VERSION 5.7 ;
  NOWIREEXTENSIONATPIN ON ;
  DIVIDERCHAR "/" ;
  BUSBITCHARS "[]" ;
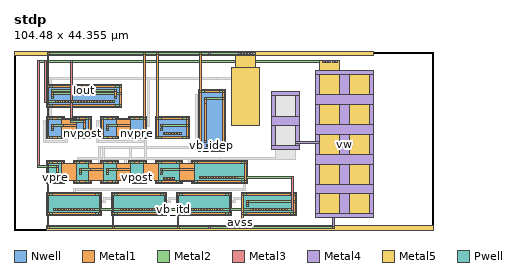
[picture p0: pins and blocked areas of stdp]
MACRO stdp
  CLASS BLOCK ;
  FOREIGN stdp ;
  ORIGIN 0.000 -0.310 ;
  SIZE 104.480 BY 44.355 ;
  PIN avdd
    USE POWER ;
    PORT
      LAYER Nwell ;
        RECT 8.000 30.865 26.860 36.465 ;
        RECT 8.000 22.965 12.490 28.565 ;
        RECT 14.790 22.965 19.280 28.565 ;
        RECT 21.580 22.965 26.070 28.565 ;
        RECT 28.370 22.965 32.860 28.565 ;
        RECT 35.160 22.965 43.620 28.565 ;
        RECT 45.920 19.920 52.580 35.210 ;
      LAYER Metal1 ;
        RECT 8.230 43.915 8.730 44.415 ;
        RECT 32.170 43.915 32.670 44.415 ;
        RECT 35.390 43.915 35.890 44.415 ;
        RECT 46.150 43.915 46.650 44.415 ;
        RECT 8.230 36.255 8.690 43.915 ;
        RECT 8.230 35.755 8.730 36.255 ;
        RECT 9.580 35.755 25.280 36.255 ;
        RECT 26.130 35.755 26.630 36.255 ;
        RECT 8.230 31.575 8.690 35.755 ;
        RECT 26.170 34.560 26.630 35.755 ;
        RECT 9.400 34.060 9.900 34.560 ;
        RECT 26.130 34.060 26.630 34.560 ;
        RECT 9.420 33.510 9.880 34.060 ;
        RECT 9.400 33.010 9.900 33.510 ;
        RECT 26.170 31.575 26.630 34.060 ;
        RECT 8.230 31.075 8.730 31.575 ;
        RECT 9.580 31.075 25.280 31.575 ;
        RECT 26.130 31.075 26.630 31.575 ;
        RECT 8.230 28.355 8.690 31.075 ;
        RECT 32.170 28.355 32.630 43.915 ;
        RECT 8.230 27.855 8.730 28.355 ;
        RECT 9.595 27.855 10.895 28.355 ;
        RECT 11.760 27.925 12.260 28.355 ;
        RECT 15.020 27.925 15.520 28.355 ;
        RECT 11.760 27.855 15.520 27.925 ;
        RECT 16.385 27.855 17.685 28.355 ;
        RECT 18.550 27.855 19.050 28.355 ;
        RECT 8.230 23.675 8.690 27.855 ;
        RECT 11.800 26.660 15.480 27.855 ;
        RECT 9.400 26.160 9.900 26.660 ;
        RECT 11.760 26.160 15.480 26.660 ;
        RECT 9.420 25.610 9.880 26.160 ;
        RECT 9.400 25.110 9.900 25.610 ;
        RECT 11.800 23.675 15.480 26.160 ;
        RECT 18.590 23.675 19.050 27.855 ;
        RECT 8.230 23.175 8.730 23.675 ;
        RECT 9.595 23.175 10.895 23.675 ;
        RECT 11.760 23.605 15.520 23.675 ;
        RECT 11.760 23.175 12.260 23.605 ;
        RECT 15.020 23.175 15.520 23.605 ;
        RECT 16.385 23.175 17.685 23.675 ;
        RECT 18.550 23.175 19.050 23.675 ;
        RECT 21.810 27.855 22.310 28.355 ;
        RECT 23.175 27.855 24.475 28.355 ;
        RECT 25.340 27.925 25.840 28.355 ;
        RECT 28.600 27.925 29.100 28.355 ;
        RECT 25.340 27.855 29.100 27.925 ;
        RECT 29.965 27.855 31.265 28.355 ;
        RECT 32.130 27.855 32.630 28.355 ;
        RECT 21.810 23.675 22.270 27.855 ;
        RECT 25.380 26.660 29.060 27.855 ;
        RECT 22.980 26.160 23.480 26.660 ;
        RECT 25.340 26.160 29.060 26.660 ;
        RECT 23.000 25.610 23.460 26.160 ;
        RECT 22.980 25.110 23.480 25.610 ;
        RECT 25.380 23.675 29.060 26.160 ;
        RECT 32.170 23.675 32.630 27.855 ;
        RECT 21.810 23.175 22.310 23.675 ;
        RECT 23.175 23.175 24.475 23.675 ;
        RECT 25.340 23.605 29.100 23.675 ;
        RECT 25.340 23.175 25.840 23.605 ;
        RECT 28.600 23.175 29.100 23.605 ;
        RECT 29.965 23.175 31.265 23.675 ;
        RECT 32.130 23.175 32.630 23.675 ;
        RECT 35.390 28.355 35.850 43.915 ;
        RECT 46.150 35.000 46.610 43.915 ;
        RECT 46.150 34.500 46.650 35.000 ;
        RECT 47.400 34.500 51.100 35.000 ;
        RECT 51.850 34.500 52.350 35.000 ;
        RECT 35.390 27.855 35.890 28.355 ;
        RECT 36.740 27.855 42.040 28.355 ;
        RECT 42.890 27.855 43.390 28.355 ;
        RECT 35.390 23.675 35.850 27.855 ;
        RECT 42.930 26.660 43.390 27.855 ;
        RECT 36.560 26.160 37.060 26.660 ;
        RECT 42.890 26.160 43.390 26.660 ;
        RECT 36.580 25.610 37.040 26.160 ;
        RECT 36.560 25.110 37.060 25.610 ;
        RECT 42.930 23.675 43.390 26.160 ;
        RECT 35.390 23.175 35.890 23.675 ;
        RECT 36.740 23.175 42.040 23.675 ;
        RECT 42.890 23.175 43.390 23.675 ;
        RECT 46.150 20.630 46.610 34.500 ;
        RECT 51.890 33.310 52.350 34.500 ;
        RECT 47.320 32.810 47.820 33.310 ;
        RECT 51.850 32.810 52.350 33.310 ;
        RECT 47.340 31.810 47.800 32.810 ;
        RECT 47.320 22.510 47.820 31.810 ;
        RECT 47.340 22.060 47.800 22.510 ;
        RECT 51.890 20.630 52.350 32.810 ;
        RECT 46.150 20.130 46.650 20.630 ;
        RECT 47.400 20.130 51.100 20.630 ;
        RECT 51.850 20.130 52.350 20.630 ;
      LAYER Metal2 ;
        RECT 8.230 43.915 60.080 44.415 ;
        RECT 8.230 35.755 26.630 36.255 ;
        RECT 9.400 34.060 26.630 34.560 ;
        RECT 46.150 34.500 52.350 35.000 ;
        RECT 9.400 33.010 9.900 33.510 ;
        RECT 47.320 32.810 52.350 33.310 ;
        RECT 8.230 31.075 26.630 31.575 ;
        RECT 8.230 27.855 12.260 28.355 ;
        RECT 15.020 27.855 19.050 28.355 ;
        RECT 21.810 27.855 25.840 28.355 ;
        RECT 28.600 27.855 32.630 28.355 ;
        RECT 35.390 27.855 43.390 28.355 ;
        RECT 9.400 26.160 12.260 26.660 ;
        RECT 22.980 26.160 25.840 26.660 ;
        RECT 36.560 26.160 43.390 26.660 ;
        RECT 9.400 25.110 9.900 25.610 ;
        RECT 22.980 25.110 23.480 25.610 ;
        RECT 36.560 25.110 37.060 25.610 ;
        RECT 8.230 23.175 12.260 23.675 ;
        RECT 15.020 23.175 19.050 23.675 ;
        RECT 21.810 23.175 25.840 23.675 ;
        RECT 28.600 23.175 32.630 23.675 ;
        RECT 35.390 23.175 43.390 23.675 ;
        RECT 47.320 22.060 47.820 32.260 ;
        RECT 46.150 20.130 52.350 20.630 ;
      LAYER Metal3 ;
        RECT 48.490 43.915 48.990 44.415 ;
        RECT 55.730 43.915 56.230 44.415 ;
        RECT 56.530 43.915 57.030 44.415 ;
        RECT 57.330 43.915 57.830 44.415 ;
        RECT 58.130 43.915 58.630 44.415 ;
        RECT 58.930 43.915 59.430 44.415 ;
      LAYER Metal4 ;
        RECT 48.490 43.915 48.990 44.415 ;
        RECT 55.730 43.915 56.230 44.415 ;
        RECT 56.530 43.915 57.030 44.415 ;
        RECT 57.330 43.915 57.830 44.415 ;
        RECT 58.130 43.915 58.630 44.415 ;
        RECT 58.930 43.915 59.430 44.415 ;
      LAYER Metal5 ;
        RECT 0.000 43.665 89.480 44.665 ;
        RECT 55.080 40.665 60.080 43.665 ;
        RECT 54.080 26.265 61.080 40.665 ;
    END
  END avdd
  PIN avss
    USE GROUND ;
    PORT
      LAYER Pwell ;
        RECT 8.000 11.910 12.490 17.510 ;
        RECT 14.790 11.910 19.280 17.510 ;
        RECT 21.580 11.910 26.070 17.510 ;
        RECT 28.370 11.910 32.860 17.510 ;
        RECT 35.160 11.855 41.820 17.565 ;
        RECT 44.120 11.910 57.980 17.510 ;
        RECT 8.000 4.010 21.860 9.610 ;
        RECT 24.160 4.010 38.020 9.610 ;
        RECT 40.320 4.010 54.180 9.610 ;
        RECT 56.480 4.010 70.340 9.610 ;
      LAYER Metal1 ;
        RECT 8.230 16.800 8.730 17.300 ;
        RECT 9.595 16.800 10.895 17.300 ;
        RECT 11.760 16.870 12.260 17.300 ;
        RECT 15.020 16.870 15.520 17.300 ;
        RECT 11.760 16.800 15.520 16.870 ;
        RECT 16.385 16.800 17.685 17.300 ;
        RECT 18.550 16.870 19.050 17.300 ;
        RECT 21.810 16.870 22.310 17.300 ;
        RECT 18.550 16.800 22.310 16.870 ;
        RECT 23.175 16.800 24.475 17.300 ;
        RECT 25.340 16.870 25.840 17.300 ;
        RECT 28.600 16.870 29.100 17.300 ;
        RECT 25.340 16.800 29.100 16.870 ;
        RECT 29.965 16.800 31.265 17.300 ;
        RECT 32.130 16.870 32.630 17.300 ;
        RECT 35.390 16.870 35.890 17.355 ;
        RECT 32.130 16.855 35.890 16.870 ;
        RECT 36.640 16.855 40.340 17.355 ;
        RECT 41.090 16.925 41.590 17.355 ;
        RECT 44.350 16.925 44.850 17.300 ;
        RECT 41.090 16.855 44.850 16.925 ;
        RECT 32.130 16.800 35.850 16.855 ;
        RECT 8.230 12.620 8.690 16.800 ;
        RECT 11.800 12.620 15.480 16.800 ;
        RECT 18.590 15.605 22.270 16.800 ;
        RECT 25.380 15.605 29.060 16.800 ;
        RECT 16.190 15.105 16.690 15.605 ;
        RECT 18.550 15.105 22.270 15.605 ;
        RECT 22.980 15.105 23.480 15.605 ;
        RECT 25.340 15.105 29.060 15.605 ;
        RECT 16.210 14.555 16.670 15.105 ;
        RECT 16.190 14.055 16.690 14.555 ;
        RECT 18.590 12.620 22.270 15.105 ;
        RECT 23.000 14.555 23.460 15.105 ;
        RECT 22.980 14.055 23.480 14.555 ;
        RECT 25.380 12.620 29.060 15.105 ;
        RECT 32.170 12.620 35.850 16.800 ;
        RECT 41.130 16.800 44.850 16.855 ;
        RECT 45.600 16.800 56.500 17.300 ;
        RECT 57.250 16.800 57.750 17.300 ;
        RECT 41.130 15.665 44.810 16.800 ;
        RECT 36.560 15.165 37.060 15.665 ;
        RECT 41.090 15.165 44.810 15.665 ;
        RECT 36.580 14.560 37.040 15.165 ;
        RECT 36.560 14.060 37.060 14.560 ;
        RECT 36.580 14.005 37.040 14.060 ;
        RECT 8.230 12.120 8.730 12.620 ;
        RECT 9.595 12.120 10.895 12.620 ;
        RECT 11.760 12.550 15.520 12.620 ;
        RECT 11.760 12.120 12.260 12.550 ;
        RECT 15.020 12.120 15.520 12.550 ;
        RECT 16.385 12.120 17.685 12.620 ;
        RECT 18.550 12.550 22.310 12.620 ;
        RECT 18.550 12.120 19.050 12.550 ;
        RECT 21.810 12.120 22.310 12.550 ;
        RECT 23.175 12.120 24.475 12.620 ;
        RECT 25.340 12.550 29.100 12.620 ;
        RECT 25.340 12.120 25.840 12.550 ;
        RECT 28.600 12.120 29.100 12.550 ;
        RECT 29.965 12.120 31.265 12.620 ;
        RECT 32.130 12.565 35.850 12.620 ;
        RECT 41.130 12.620 44.810 15.165 ;
        RECT 57.290 12.620 57.750 16.800 ;
        RECT 41.130 12.565 44.850 12.620 ;
        RECT 32.130 12.550 35.890 12.565 ;
        RECT 32.130 12.120 32.630 12.550 ;
        RECT 8.230 9.400 8.690 12.120 ;
        RECT 35.390 12.065 35.890 12.550 ;
        RECT 36.640 12.065 40.340 12.565 ;
        RECT 41.090 12.495 44.850 12.565 ;
        RECT 41.090 12.065 41.590 12.495 ;
        RECT 44.350 12.120 44.850 12.495 ;
        RECT 45.600 12.120 56.500 12.620 ;
        RECT 57.250 12.120 57.750 12.620 ;
        RECT 8.230 8.900 8.730 9.400 ;
        RECT 9.480 8.900 20.380 9.400 ;
        RECT 21.130 8.900 21.630 9.400 ;
        RECT 8.230 4.720 8.690 8.900 ;
        RECT 21.170 4.720 21.630 8.900 ;
        RECT 8.230 4.220 8.730 4.720 ;
        RECT 9.480 4.220 20.380 4.720 ;
        RECT 21.130 4.220 21.630 4.720 ;
        RECT 24.390 8.900 24.890 9.400 ;
        RECT 25.640 8.900 36.540 9.400 ;
        RECT 37.290 8.900 37.790 9.400 ;
        RECT 24.390 4.720 24.850 8.900 ;
        RECT 37.330 4.720 37.790 8.900 ;
        RECT 24.390 4.220 24.890 4.720 ;
        RECT 25.640 4.220 36.540 4.720 ;
        RECT 37.290 4.220 37.790 4.720 ;
        RECT 40.550 8.900 41.050 9.400 ;
        RECT 41.800 8.900 52.700 9.400 ;
        RECT 53.450 8.900 53.950 9.400 ;
        RECT 40.550 4.720 41.010 8.900 ;
        RECT 53.490 4.720 53.950 8.900 ;
        RECT 40.550 4.220 41.050 4.720 ;
        RECT 41.800 4.220 52.700 4.720 ;
        RECT 53.450 4.220 53.950 4.720 ;
        RECT 56.710 8.900 57.210 9.400 ;
        RECT 57.960 8.900 68.860 9.400 ;
        RECT 69.610 8.900 70.110 9.400 ;
        RECT 56.710 4.720 57.170 8.900 ;
        RECT 69.650 7.705 70.110 8.900 ;
        RECT 57.880 7.205 58.380 7.705 ;
        RECT 69.610 7.205 70.110 7.705 ;
        RECT 57.900 6.655 58.360 7.205 ;
        RECT 57.880 6.155 58.380 6.655 ;
        RECT 69.650 4.720 70.110 7.205 ;
        RECT 56.710 4.220 57.210 4.720 ;
        RECT 57.960 4.220 68.860 4.720 ;
        RECT 69.610 4.220 70.110 4.720 ;
        RECT 8.230 1.060 8.690 4.220 ;
        RECT 24.390 1.060 24.850 4.220 ;
        RECT 40.550 1.060 41.010 4.220 ;
        RECT 56.710 1.060 57.170 4.220 ;
        RECT 8.230 0.560 8.730 1.060 ;
        RECT 24.390 0.560 24.890 1.060 ;
        RECT 40.550 0.560 41.050 1.060 ;
        RECT 56.670 0.560 57.170 1.060 ;
      LAYER Metal2 ;
        RECT 8.230 16.800 12.260 17.300 ;
        RECT 15.020 16.800 19.050 17.300 ;
        RECT 21.810 16.800 25.840 17.300 ;
        RECT 28.600 16.800 32.630 17.300 ;
        RECT 35.390 16.855 41.590 17.355 ;
        RECT 44.350 16.800 57.750 17.300 ;
        RECT 16.190 15.105 19.050 15.605 ;
        RECT 22.980 15.105 25.840 15.605 ;
        RECT 36.560 15.165 41.590 15.665 ;
        RECT 16.190 14.055 16.690 14.555 ;
        RECT 22.980 14.055 23.480 14.555 ;
        RECT 36.560 14.005 37.060 14.615 ;
        RECT 8.230 12.120 12.260 12.620 ;
        RECT 15.020 12.120 19.050 12.620 ;
        RECT 21.810 12.120 25.840 12.620 ;
        RECT 28.600 12.120 32.630 12.620 ;
        RECT 35.390 12.065 41.590 12.565 ;
        RECT 44.350 12.120 57.750 12.620 ;
        RECT 8.230 8.900 21.630 9.400 ;
        RECT 24.390 8.900 37.790 9.400 ;
        RECT 40.550 8.900 53.950 9.400 ;
        RECT 56.710 8.900 70.110 9.400 ;
        RECT 57.880 7.205 70.110 7.705 ;
        RECT 57.880 6.155 58.380 6.655 ;
        RECT 8.230 4.220 21.630 4.720 ;
        RECT 24.390 4.220 37.790 4.720 ;
        RECT 40.550 4.220 53.950 4.720 ;
        RECT 56.710 4.220 70.110 4.720 ;
        RECT 8.230 0.560 79.630 1.060 ;
      LAYER Metal3 ;
        RECT 48.490 0.560 48.990 1.060 ;
        RECT 79.130 0.560 79.630 1.060 ;
      LAYER Metal4 ;
        RECT 75.080 38.910 89.480 39.910 ;
        RECT 64.080 33.665 71.080 34.665 ;
        RECT 64.080 28.665 65.080 33.665 ;
        RECT 70.080 28.665 71.080 33.665 ;
        RECT 64.080 26.265 71.080 28.665 ;
        RECT 64.080 21.265 65.080 26.265 ;
        RECT 70.080 22.415 71.080 26.265 ;
        RECT 75.080 33.910 76.080 38.910 ;
        RECT 81.080 33.910 83.480 38.910 ;
        RECT 88.480 33.910 89.480 38.910 ;
        RECT 75.080 31.510 89.480 33.910 ;
        RECT 75.080 26.510 76.080 31.510 ;
        RECT 81.080 26.510 83.480 31.510 ;
        RECT 88.480 26.510 89.480 31.510 ;
        RECT 75.080 24.110 89.480 26.510 ;
        RECT 75.080 22.415 76.080 24.110 ;
        RECT 70.080 21.915 76.080 22.415 ;
        RECT 70.080 21.265 71.080 21.915 ;
        RECT 64.080 20.265 71.080 21.265 ;
        RECT 75.080 19.110 76.080 21.915 ;
        RECT 81.080 19.110 83.480 24.110 ;
        RECT 88.480 19.110 89.480 24.110 ;
        RECT 75.080 16.710 89.480 19.110 ;
        RECT 75.080 11.710 76.080 16.710 ;
        RECT 81.080 11.710 83.480 16.710 ;
        RECT 88.480 11.710 89.480 16.710 ;
        RECT 75.080 9.310 89.480 11.710 ;
        RECT 75.080 4.310 76.080 9.310 ;
        RECT 81.080 4.310 83.480 9.310 ;
        RECT 88.480 4.310 89.480 9.310 ;
        RECT 75.080 3.310 89.480 4.310 ;
        RECT 48.490 0.560 48.990 1.060 ;
        RECT 79.130 0.560 79.630 3.310 ;
      LAYER Metal5 ;
        RECT 8.000 0.310 104.480 1.310 ;
    END
  END avss
  PIN nvpost
    ANTENNAGATEAREA 0.315000 ;
    PORT
      LAYER Metal1 ;
        RECT 16.785 24.070 17.285 24.570 ;
      LAYER Metal2 ;
        RECT 16.720 24.070 17.350 24.570 ;
      LAYER Metal3 ;
        RECT 16.850 24.070 17.350 24.570 ;
      LAYER Metal4 ;
        RECT 16.850 24.070 17.350 24.570 ;
    END
  END nvpost
  PIN nvpre
    ANTENNAGATEAREA 0.315000 ;
    PORT
      LAYER Metal1 ;
        RECT 30.365 24.070 30.865 24.570 ;
      LAYER Metal2 ;
        RECT 30.300 24.070 30.930 24.570 ;
      LAYER Metal3 ;
        RECT 30.430 24.070 30.930 24.570 ;
      LAYER Metal4 ;
        RECT 30.430 24.070 30.930 24.570 ;
    END
  END nvpre
  PIN vpost
    ANTENNAGATEAREA 0.315000 ;
    PORT
      LAYER Metal1 ;
        RECT 30.365 13.015 30.865 13.515 ;
      LAYER Metal2 ;
        RECT 30.300 13.015 30.930 13.515 ;
      LAYER Metal3 ;
        RECT 30.430 13.015 30.930 13.515 ;
      LAYER Metal4 ;
        RECT 30.430 13.015 30.930 13.515 ;
    END
  END vpost
  PIN vpre
    ANTENNAGATEAREA 0.315000 ;
    PORT
      LAYER Metal1 ;
        RECT 9.995 13.015 10.495 13.515 ;
      LAYER Metal2 ;
        RECT 9.930 13.015 10.560 13.515 ;
      LAYER Metal3 ;
        RECT 10.060 13.015 10.560 13.515 ;
      LAYER Metal4 ;
        RECT 10.060 13.015 10.560 13.515 ;
    END
  END vpre
  PIN vb_idep
    ANTENNAGATEAREA 28.559999 ;
    PORT
      LAYER Metal1 ;
        RECT 48.200 21.020 48.700 21.520 ;
        RECT 49.000 21.020 49.500 21.520 ;
        RECT 49.800 21.020 50.300 21.520 ;
      LAYER Metal2 ;
        RECT 47.850 21.020 50.650 21.520 ;
      LAYER Metal3 ;
        RECT 50.150 21.020 50.650 21.520 ;
      LAYER Metal4 ;
        RECT 50.150 21.020 50.650 21.520 ;
    END
  END vb_idep
  PIN vb_itd
    ANTENNAGATEAREA 25.000000 ;
    PORT
      LAYER Metal1 ;
        RECT 46.400 13.015 46.900 13.515 ;
        RECT 47.200 13.015 47.700 13.515 ;
        RECT 48.000 13.015 48.500 13.515 ;
        RECT 48.800 13.015 49.300 13.515 ;
        RECT 49.600 13.015 50.100 13.515 ;
        RECT 50.400 13.015 50.900 13.515 ;
        RECT 51.200 13.015 51.700 13.515 ;
        RECT 52.000 13.015 52.500 13.515 ;
        RECT 52.800 13.015 53.300 13.515 ;
        RECT 53.600 13.015 54.100 13.515 ;
        RECT 54.400 13.015 54.900 13.515 ;
        RECT 55.200 13.015 55.700 13.515 ;
        RECT 10.280 5.115 10.780 5.615 ;
        RECT 11.080 5.115 11.580 5.615 ;
        RECT 11.880 5.115 12.380 5.615 ;
        RECT 12.680 5.115 13.180 5.615 ;
        RECT 13.480 5.115 13.980 5.615 ;
        RECT 14.280 5.115 14.780 5.615 ;
        RECT 15.080 5.115 15.580 5.615 ;
        RECT 15.880 5.115 16.380 5.615 ;
        RECT 16.680 5.115 17.180 5.615 ;
        RECT 17.480 5.115 17.980 5.615 ;
        RECT 18.280 5.115 18.780 5.615 ;
        RECT 19.080 5.115 19.580 5.615 ;
        RECT 26.440 5.115 26.940 5.615 ;
        RECT 27.240 5.115 27.740 5.615 ;
        RECT 28.040 5.115 28.540 5.615 ;
        RECT 28.840 5.115 29.340 5.615 ;
        RECT 29.640 5.115 30.140 5.615 ;
        RECT 30.440 5.115 30.940 5.615 ;
        RECT 31.240 5.115 31.740 5.615 ;
        RECT 32.040 5.115 32.540 5.615 ;
        RECT 32.840 5.115 33.340 5.615 ;
        RECT 33.640 5.115 34.140 5.615 ;
        RECT 34.440 5.115 34.940 5.615 ;
        RECT 35.240 5.115 35.740 5.615 ;
        RECT 42.600 5.115 43.100 5.615 ;
        RECT 43.400 5.115 43.900 5.615 ;
        RECT 44.200 5.115 44.700 5.615 ;
        RECT 45.000 5.115 45.500 5.615 ;
        RECT 45.800 5.115 46.300 5.615 ;
        RECT 46.600 5.115 47.100 5.615 ;
        RECT 47.400 5.115 47.900 5.615 ;
        RECT 48.200 5.115 48.700 5.615 ;
        RECT 49.000 5.115 49.500 5.615 ;
        RECT 49.800 5.115 50.300 5.615 ;
        RECT 50.600 5.115 51.100 5.615 ;
        RECT 51.400 5.115 51.900 5.615 ;
        RECT 58.760 5.115 59.260 5.615 ;
        RECT 59.560 5.115 60.060 5.615 ;
        RECT 60.360 5.115 60.860 5.615 ;
        RECT 61.160 5.115 61.660 5.615 ;
        RECT 61.960 5.115 62.460 5.615 ;
        RECT 62.760 5.115 63.260 5.615 ;
        RECT 63.560 5.115 64.060 5.615 ;
        RECT 64.360 5.115 64.860 5.615 ;
        RECT 65.160 5.115 65.660 5.615 ;
        RECT 65.960 5.115 66.460 5.615 ;
        RECT 66.760 5.115 67.260 5.615 ;
        RECT 67.560 5.115 68.060 5.615 ;
      LAYER Metal2 ;
        RECT 46.050 13.015 69.410 13.515 ;
        RECT 9.930 5.115 69.410 5.615 ;
      LAYER Metal3 ;
        RECT 19.430 5.115 19.930 5.615 ;
        RECT 68.910 5.115 69.410 13.515 ;
      LAYER Metal4 ;
        RECT 19.430 5.115 19.930 5.615 ;
    END
  END vb_itd
  PIN vb_itp
    ANTENNAGATEAREA 2.300000 ;
    PORT
      LAYER Metal1 ;
        RECT 37.540 24.070 38.040 24.570 ;
        RECT 38.340 24.070 38.840 24.570 ;
        RECT 39.140 24.070 39.640 24.570 ;
        RECT 39.940 24.070 40.440 24.570 ;
        RECT 40.740 24.070 41.240 24.570 ;
      LAYER Metal2 ;
        RECT 37.090 24.070 41.690 24.570 ;
      LAYER Metal3 ;
        RECT 41.190 24.070 41.690 24.570 ;
      LAYER Metal4 ;
        RECT 41.190 24.070 41.690 24.570 ;
    END
  END vb_itp
  PIN vb_pot
    ANTENNAGATEAREA 1.708000 ;
    PORT
      LAYER Metal1 ;
        RECT 37.440 12.960 37.940 13.460 ;
        RECT 38.240 12.960 38.740 13.460 ;
        RECT 39.040 12.960 39.540 13.460 ;
      LAYER Metal2 ;
        RECT 37.090 12.960 39.890 13.460 ;
      LAYER Metal3 ;
        RECT 39.390 12.960 39.890 13.460 ;
      LAYER Metal4 ;
        RECT 39.390 12.960 39.890 13.460 ;
    END
  END vb_pot
  PIN vw
    ANTENNAGATEAREA 7.500000 ;
    ANTENNADIFFAREA 0.600000 ;
    PORT
      LAYER Metal1 ;
        RECT 10.380 31.970 10.880 32.470 ;
        RECT 11.180 31.970 11.680 32.470 ;
        RECT 11.980 31.970 12.480 32.470 ;
        RECT 12.780 31.970 13.280 32.470 ;
        RECT 13.580 31.970 14.080 32.470 ;
        RECT 14.380 31.970 14.880 32.470 ;
        RECT 15.180 31.970 15.680 32.470 ;
        RECT 15.980 31.970 16.480 32.470 ;
        RECT 16.780 31.970 17.280 32.470 ;
        RECT 17.580 31.970 18.080 32.470 ;
        RECT 18.380 31.970 18.880 32.470 ;
        RECT 19.180 31.970 19.680 32.470 ;
        RECT 19.980 31.970 20.480 32.470 ;
        RECT 20.780 31.970 21.280 32.470 ;
        RECT 21.580 31.970 22.080 32.470 ;
        RECT 22.380 31.970 22.880 32.470 ;
        RECT 23.180 31.970 23.680 32.470 ;
        RECT 23.980 31.970 24.480 32.470 ;
        RECT 17.380 26.960 17.880 27.460 ;
        RECT 17.400 25.610 17.860 26.960 ;
        RECT 17.380 25.110 17.880 25.610 ;
        RECT 10.590 15.905 11.090 16.405 ;
        RECT 10.610 14.555 11.070 15.905 ;
        RECT 10.590 14.055 11.090 14.555 ;
      LAYER Metal2 ;
        RECT 5.900 41.960 81.080 42.460 ;
        RECT 7.630 31.970 24.930 32.470 ;
        RECT 13.940 26.960 17.880 27.460 ;
        RECT 17.380 25.110 17.880 25.610 ;
        RECT 5.900 15.905 11.090 16.405 ;
        RECT 10.590 14.055 11.090 14.555 ;
      LAYER Metal3 ;
        RECT 5.900 15.905 6.400 42.460 ;
        RECT 7.630 31.970 8.130 42.460 ;
        RECT 13.940 26.960 14.440 42.460 ;
        RECT 76.730 41.960 77.230 42.460 ;
        RECT 77.530 41.960 78.030 42.460 ;
        RECT 78.330 41.960 78.830 42.460 ;
        RECT 79.130 41.960 79.630 42.460 ;
        RECT 79.930 41.960 80.430 42.460 ;
      LAYER Metal4 ;
        RECT 13.940 41.960 14.440 42.460 ;
        RECT 76.730 41.960 77.230 42.460 ;
        RECT 77.530 41.960 78.030 42.460 ;
        RECT 78.330 41.960 78.830 42.460 ;
        RECT 79.130 41.960 79.630 42.460 ;
        RECT 79.930 41.960 80.430 42.460 ;
      LAYER Metal5 ;
        RECT 76.080 39.910 81.080 42.460 ;
        RECT 75.080 3.310 89.480 39.910 ;
    END
  END vw
  PIN Iout
    ANTENNADIFFAREA 0.300000 ;
    PORT
      LAYER Metal1 ;
        RECT 24.960 34.860 25.460 35.360 ;
        RECT 24.980 33.510 25.440 34.860 ;
        RECT 24.960 33.010 25.460 33.510 ;
      LAYER Metal2 ;
        RECT 9.400 34.860 25.460 35.360 ;
        RECT 24.960 33.010 25.460 33.510 ;
      LAYER Metal3 ;
        RECT 24.960 34.860 25.460 35.360 ;
      LAYER Metal4 ;
        RECT 24.960 34.860 25.460 35.360 ;
    END
  END Iout
  OBS
      LAYER Metal1 ;
        RECT 50.680 33.610 51.180 34.110 ;
        RECT 50.700 31.810 51.160 33.610 ;
        RECT 10.590 26.960 11.090 27.460 ;
        RECT 24.170 26.960 24.670 27.460 ;
        RECT 30.960 26.960 31.460 27.460 ;
        RECT 41.720 26.960 42.220 27.460 ;
        RECT 10.610 25.610 11.070 26.960 ;
        RECT 16.190 26.160 16.690 26.660 ;
        RECT 16.210 25.610 16.670 26.160 ;
        RECT 24.190 25.610 24.650 26.960 ;
        RECT 29.770 26.160 30.270 26.660 ;
        RECT 29.790 25.610 30.250 26.160 ;
        RECT 30.980 25.610 31.440 26.960 ;
        RECT 41.740 25.610 42.200 26.960 ;
        RECT 10.590 25.110 11.090 25.610 ;
        RECT 16.190 25.110 16.690 25.610 ;
        RECT 24.170 25.110 24.670 25.610 ;
        RECT 29.770 25.110 30.270 25.610 ;
        RECT 30.960 25.110 31.460 25.610 ;
        RECT 41.720 25.110 42.220 25.610 ;
        RECT 9.995 24.070 10.495 24.570 ;
        RECT 23.575 24.070 24.075 24.570 ;
        RECT 50.680 22.510 51.180 31.810 ;
        RECT 50.700 22.060 51.160 22.510 ;
        RECT 17.380 15.905 17.880 16.405 ;
        RECT 24.170 15.905 24.670 16.405 ;
        RECT 30.960 15.905 31.460 16.405 ;
        RECT 39.920 15.965 40.420 16.465 ;
        RECT 9.400 15.105 9.900 15.605 ;
        RECT 9.420 14.555 9.880 15.105 ;
        RECT 17.400 14.555 17.860 15.905 ;
        RECT 24.190 14.555 24.650 15.905 ;
        RECT 29.770 15.105 30.270 15.605 ;
        RECT 29.790 14.555 30.250 15.105 ;
        RECT 30.980 14.555 31.440 15.905 ;
        RECT 39.940 14.560 40.400 15.965 ;
        RECT 56.080 15.905 56.580 16.405 ;
        RECT 45.520 15.105 46.020 15.605 ;
        RECT 9.400 14.055 9.900 14.555 ;
        RECT 17.380 14.055 17.880 14.555 ;
        RECT 24.170 14.055 24.670 14.555 ;
        RECT 29.770 14.055 30.270 14.555 ;
        RECT 30.960 14.055 31.460 14.555 ;
        RECT 39.920 14.060 40.420 14.560 ;
        RECT 45.540 14.555 46.000 15.105 ;
        RECT 56.100 14.555 56.560 15.905 ;
        RECT 39.940 14.005 40.400 14.060 ;
        RECT 45.520 14.055 46.020 14.555 ;
        RECT 56.080 14.055 56.580 14.555 ;
        RECT 16.785 13.015 17.285 13.515 ;
        RECT 23.575 13.015 24.075 13.515 ;
        RECT 19.960 8.005 20.460 8.505 ;
        RECT 36.120 8.005 36.620 8.505 ;
        RECT 52.280 8.005 52.780 8.505 ;
        RECT 68.440 8.005 68.940 8.505 ;
        RECT 9.400 7.205 9.900 7.705 ;
        RECT 9.420 6.655 9.880 7.205 ;
        RECT 19.980 6.655 20.440 8.005 ;
        RECT 25.560 7.205 26.060 7.705 ;
        RECT 25.580 6.655 26.040 7.205 ;
        RECT 36.140 6.655 36.600 8.005 ;
        RECT 41.720 7.205 42.220 7.705 ;
        RECT 41.740 6.655 42.200 7.205 ;
        RECT 52.300 6.655 52.760 8.005 ;
        RECT 68.460 6.655 68.920 8.005 ;
        RECT 9.400 6.155 9.900 6.655 ;
        RECT 19.960 6.155 20.460 6.655 ;
        RECT 25.560 6.155 26.060 6.655 ;
        RECT 36.120 6.155 36.620 6.655 ;
        RECT 41.720 6.155 42.220 6.655 ;
        RECT 52.280 6.155 52.780 6.655 ;
        RECT 68.440 6.155 68.940 6.655 ;
      LAYER Metal2 ;
        RECT 8.930 37.715 50.980 38.215 ;
        RECT 45.070 33.610 51.180 34.110 ;
        RECT 7.400 26.960 11.090 27.460 ;
        RECT 20.480 26.960 24.670 27.460 ;
        RECT 26.690 26.960 31.460 27.460 ;
        RECT 35.560 26.960 42.220 27.460 ;
        RECT 12.840 26.160 17.880 26.660 ;
        RECT 29.770 26.160 33.710 26.660 ;
        RECT 10.590 25.110 11.090 25.610 ;
        RECT 16.190 25.110 16.690 25.610 ;
        RECT 24.170 25.110 24.670 25.610 ;
        RECT 29.770 25.110 30.270 25.610 ;
        RECT 30.960 25.110 31.460 25.610 ;
        RECT 41.720 25.110 42.220 25.610 ;
        RECT 8.930 24.070 10.560 24.570 ;
        RECT 23.510 24.070 27.190 24.570 ;
        RECT 7.400 21.960 13.340 22.460 ;
        RECT 20.480 21.960 32.920 22.460 ;
        RECT 50.680 22.060 51.180 32.260 ;
        RECT 21.010 20.610 45.570 21.110 ;
        RECT 15.720 17.955 70.080 18.455 ;
        RECT 12.840 15.905 17.880 16.405 ;
        RECT 21.980 15.905 24.670 16.405 ;
        RECT 28.770 15.905 31.460 16.405 ;
        RECT 32.420 15.965 40.420 16.465 ;
        RECT 43.520 15.905 56.580 16.405 ;
        RECT 9.400 15.105 13.340 15.605 ;
        RECT 27.470 15.105 31.460 15.605 ;
        RECT 45.520 15.105 57.580 15.605 ;
        RECT 9.400 14.055 9.900 14.555 ;
        RECT 17.380 14.055 17.880 14.555 ;
        RECT 24.170 14.055 24.670 14.555 ;
        RECT 29.770 14.055 30.270 14.555 ;
        RECT 30.960 14.055 31.460 14.555 ;
        RECT 39.920 14.005 40.420 14.615 ;
        RECT 45.520 14.055 46.020 14.555 ;
        RECT 56.080 14.055 56.580 14.555 ;
        RECT 15.720 13.015 17.350 13.515 ;
        RECT 21.010 13.015 24.140 13.515 ;
        RECT 14.680 10.055 57.580 10.555 ;
        RECT 9.400 8.005 20.460 8.505 ;
        RECT 22.210 8.005 36.620 8.505 ;
        RECT 38.370 8.005 52.780 8.505 ;
        RECT 54.530 8.005 68.940 8.505 ;
        RECT 9.400 7.205 22.710 7.705 ;
        RECT 25.560 7.205 38.870 7.705 ;
        RECT 41.720 7.205 55.030 7.705 ;
        RECT 9.400 6.155 9.900 6.655 ;
        RECT 19.960 6.155 20.460 6.655 ;
        RECT 25.560 6.155 26.060 6.655 ;
        RECT 36.120 6.155 36.620 6.655 ;
        RECT 41.720 6.155 42.220 6.655 ;
        RECT 52.280 6.155 52.780 6.655 ;
        RECT 68.440 6.155 68.940 6.655 ;
      LAYER Metal3 ;
        RECT 7.400 21.960 7.900 27.460 ;
        RECT 8.930 24.070 9.430 38.215 ;
        RECT 12.840 21.960 13.340 26.660 ;
        RECT 20.480 21.960 20.980 27.460 ;
        RECT 26.690 24.070 27.190 27.460 ;
        RECT 33.210 26.160 33.710 38.215 ;
        RECT 35.560 26.960 36.060 38.215 ;
        RECT 50.480 37.715 50.980 38.215 ;
        RECT 12.840 15.105 13.340 16.405 ;
        RECT 15.720 13.015 16.220 18.455 ;
        RECT 21.010 13.015 21.510 21.110 ;
        RECT 21.980 15.905 22.480 21.110 ;
        RECT 27.470 15.105 27.970 18.455 ;
        RECT 28.770 15.905 29.270 21.110 ;
        RECT 32.420 15.965 32.920 22.460 ;
        RECT 45.070 20.610 45.570 34.110 ;
        RECT 43.520 15.905 44.020 18.455 ;
        RECT 50.800 17.955 51.300 18.455 ;
        RECT 65.730 17.955 66.230 18.455 ;
        RECT 66.530 17.955 67.030 18.455 ;
        RECT 67.330 17.955 67.830 18.455 ;
        RECT 68.130 17.955 68.630 18.455 ;
        RECT 68.930 17.955 69.430 18.455 ;
        RECT 14.680 8.005 15.180 10.555 ;
        RECT 57.080 10.055 57.580 15.605 ;
        RECT 22.210 7.205 22.710 8.505 ;
        RECT 38.370 7.205 38.870 8.505 ;
        RECT 54.530 7.205 55.030 8.505 ;
      LAYER Metal4 ;
        RECT 54.080 39.665 61.080 40.665 ;
        RECT 54.080 38.215 55.080 39.665 ;
        RECT 50.480 37.715 55.080 38.215 ;
        RECT 54.080 34.665 55.080 37.715 ;
        RECT 60.080 34.665 61.080 39.665 ;
        RECT 54.080 32.265 61.080 34.665 ;
        RECT 54.080 27.265 55.080 32.265 ;
        RECT 60.080 27.265 61.080 32.265 ;
        RECT 54.080 26.265 61.080 27.265 ;
        RECT 65.730 17.955 66.230 18.455 ;
        RECT 66.530 17.955 67.030 18.455 ;
        RECT 67.330 17.955 67.830 18.455 ;
        RECT 68.130 17.955 68.630 18.455 ;
        RECT 68.930 17.955 69.430 18.455 ;
      LAYER Metal5 ;
        RECT 64.080 20.265 71.080 34.665 ;
        RECT 65.080 17.955 70.080 20.265 ;
  END
END stdp
END LIBRARY

